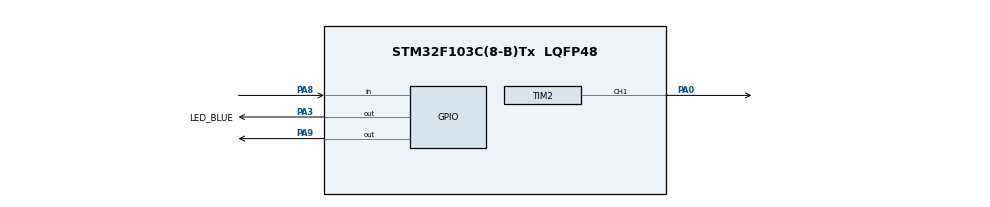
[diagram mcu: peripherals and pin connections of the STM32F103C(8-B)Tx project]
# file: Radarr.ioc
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Mcu.Family=STM32F1
Mcu.Name=STM32F103C(8-B)Tx
Mcu.Package=LQFP48
NVIC.PriorityGroup=NVIC_PRIORITYGROUP_4
PA0-WKUP.Signal=S_TIM2_CH1_ETR
PA13.Mode=Serial_Wire
PA13.Signal=SYS_JTMS-SWDIO
PA14.Mode=Serial_Wire
PA14.Signal=SYS_JTCK-SWCLK
PA3.GPIO_Label=LED_BLUE
PA3.Signal=GPIO_Output
PA8.Signal=GPIO_Input
PA9.Signal=GPIO_Output
PD0-OSC_IN.Mode=HSE-External-Oscillator
PD0-OSC_IN.Signal=RCC_OSC_IN
PD1-OSC_OUT.Mode=HSE-External-Oscillator
PD1-OSC_OUT.Signal=RCC_OSC_OUT
ProjectManager.HeapSize=0x200
ProjectManager.StackSize=0x400
ProjectManager.TargetToolchain=STM32CubeIDE
RCC.APB1Freq_Value=8000000
RCC.APB2Freq_Value=8000000
SH.S_TIM2_CH1_ETR.0=TIM2_CH1,PWM Generation1 CH1
TIM1.Prescaler=71
TIM2.Channel-PWM\ Generation1\ CH1=TIM_CHANNEL_1
TIM2.Prescaler=20
VP_TIM1_VS_ClockSourceINT.Mode=Internal
VP_TIM2_VS_ClockSourceINT.Mode=Internal
board=custom

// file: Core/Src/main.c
/* USER CODE BEGIN Header */
/**
  ******************************************************************************
  * @file           : main.c
  * @brief          : Main program body
  ******************************************************************************
  * @attention
  *
  * Copyright (c) 2025 STMicroelectronics.
  * All rights reserved.
  *
  * This software is licensed under terms that can be found in the LICENSE file
  * in the root directory of this software component.
  * If no LICENSE file comes with this software, it is provided AS-IS.
  *
  ******************************************************************************
  */
/* USER CODE END Header */
#include "main.h"

/* USER CODE BEGIN Includes */
#include <stdbool.h>
/* USER CODE END Includes */

/* USER CODE BEGIN PD */
#define TRIG_PIN GPIO_PIN_9
#define TRIG_PORT GPIOA
#define	ECHO_PIN GPIO_PIN_8
#define	ECHO_PORT GPIOA
/* USER CODE END PD */

TIM_HandleTypeDef htim1;
TIM_HandleTypeDef htim2;

/* USER CODE BEGIN PV */

//servo var
int32_t pwm_val = 0;
bool direction = 0;
//servo var

//distance meter var
uint32_t pMillis;
uint32_t Value1 = 0;
uint32_t Value2 = 0;
uint16_t Distance = 0; //cm
//distance meter var

/* USER CODE END PV */

void SystemClock_Config(void);
static void MX_GPIO_Init(void);
static void MX_TIM1_Init(void);
static void MX_TIM2_Init(void);
/* USER CODE BEGIN PFP */
void calculate_distance();
/* USER CODE END PFP */

int main(void)
{

  /* MCU Configuration--------------------------------------------------------*/

  /* Reset of all peripherals, Initializes the Flash interface and the Systick. */
  HAL_Init();

  /* Configure the system clock */
  SystemClock_Config();

  /* Initialize all configured peripherals */
  MX_GPIO_Init();
  MX_TIM1_Init();
  MX_TIM2_Init();
  /* USER CODE BEGIN 2 */

  HAL_TIM_PWM_Start(&htim2, TIM_CHANNEL_1);

  HAL_TIM_Base_Start(&htim1);
  HAL_GPIO_WritePin(TRIG_PORT, TRIG_PIN, GPIO_PIN_RESET);

  /* USER CODE END 2 */

  /* Infinite loop */
  /* USER CODE BEGIN WHILE */
  while (1)
  {
	  if(pwm_val < 1920){
		  direction = 1;
	  }
	  else if(pwm_val > 7680){
		  direction = 0;
	  }
	  if(direction) {
		  pwm_val += 5;
	  }
	  else {
		  pwm_val -= 5;
	  }

	  __HAL_TIM_SET_COMPARE(&htim2, TIM_CHANNEL_1, pwm_val);
	  calculate_distance();
	  HAL_Delay(1);

    /* USER CODE END WHILE */

  }
}

void calculate_distance() {
	HAL_GPIO_WritePin(TRIG_PORT, TRIG_PIN, GPIO_PIN_RESET);
	HAL_Delay(2); // Stabilizasyon için küçük gecikme
	HAL_GPIO_WritePin(TRIG_PORT, TRIG_PIN, GPIO_PIN_SET);
	HAL_Delay(0.01); // 10 mikro saniye TRIG HIGH
    HAL_GPIO_WritePin(TRIG_PORT, TRIG_PIN, GPIO_PIN_RESET);

	uint32_t timeout = HAL_GetTick();
	while (HAL_GPIO_ReadPin(ECHO_PORT, ECHO_PIN) == GPIO_PIN_RESET) {
	    if (HAL_GetTick() - timeout > 5) break; // 5 ms timeout
	}
	Value1 = __HAL_TIM_GET_COUNTER(&htim1);

	timeout = HAL_GetTick();
	while (HAL_GPIO_ReadPin(ECHO_PORT, ECHO_PIN) == GPIO_PIN_SET) {
	    if (HAL_GetTick() - timeout > 20) break; // 20 ms timeout
	}
	Value2 = __HAL_TIM_GET_COUNTER(&htim1);

	int32_t time_diff = Value2 - Value1;
	if (time_diff < 0) time_diff += __HAL_TIM_GET_AUTORELOAD(&htim1); // Timer taşmasına karşı
	Distance = (float)time_diff * 0.034 / 2;
	HAL_GPIO_WritePin(GPIOA, GPIO_PIN_3, (Distance < 5) ? GPIO_PIN_SET : GPIO_PIN_RESET);
}

void SystemClock_Config(void)
{
  RCC_OscInitTypeDef RCC_OscInitStruct = {0};
  RCC_ClkInitTypeDef RCC_ClkInitStruct = {0};

  /** Initializes the RCC Oscillators according to the specified parameters
  * in the RCC_OscInitTypeDef structure.
  */
  RCC_OscInitStruct.OscillatorType = RCC_OSCILLATORTYPE_HSE;
  RCC_OscInitStruct.HSEState = RCC_HSE_ON;
  RCC_OscInitStruct.HSEPredivValue = RCC_HSE_PREDIV_DIV1;
  RCC_OscInitStruct.HSIState = RCC_HSI_ON;
  RCC_OscInitStruct.PLL.PLLState = RCC_PLL_ON;
  RCC_OscInitStruct.PLL.PLLSource = RCC_PLLSOURCE_HSE;
  RCC_OscInitStruct.PLL.PLLMUL = RCC_PLL_MUL9;
  if (HAL_RCC_OscConfig(&RCC_OscInitStruct) != HAL_OK)
  {
    Error_Handler();
  }

  /** Initializes the CPU, AHB and APB buses clocks
  */
  RCC_ClkInitStruct.ClockType = RCC_CLOCKTYPE_HCLK|RCC_CLOCKTYPE_SYSCLK
                              |RCC_CLOCKTYPE_PCLK1|RCC_CLOCKTYPE_PCLK2;
  RCC_ClkInitStruct.SYSCLKSource = RCC_SYSCLKSOURCE_PLLCLK;
  RCC_ClkInitStruct.AHBCLKDivider = RCC_SYSCLK_DIV1;
  RCC_ClkInitStruct.APB1CLKDivider = RCC_HCLK_DIV2;
  RCC_ClkInitStruct.APB2CLKDivider = RCC_HCLK_DIV1;

  if (HAL_RCC_ClockConfig(&RCC_ClkInitStruct, FLASH_LATENCY_2) != HAL_OK)
  {
    Error_Handler();
  }
}

static void MX_TIM1_Init(void)
{

  TIM_ClockConfigTypeDef sClockSourceConfig = {0};
  TIM_MasterConfigTypeDef sMasterConfig = {0};

  htim1.Instance = TIM1;
  htim1.Init.Prescaler = 71;
  htim1.Init.CounterMode = TIM_COUNTERMODE_UP;
  htim1.Init.Period = 65535;
  htim1.Init.ClockDivision = TIM_CLOCKDIVISION_DIV1;
  htim1.Init.RepetitionCounter = 0;
  htim1.Init.AutoReloadPreload = TIM_AUTORELOAD_PRELOAD_DISABLE;
  if (HAL_TIM_Base_Init(&htim1) != HAL_OK)
  {
    Error_Handler();
  }
  sClockSourceConfig.ClockSource = TIM_CLOCKSOURCE_INTERNAL;
  if (HAL_TIM_ConfigClockSource(&htim1, &sClockSourceConfig) != HAL_OK)
  {
    Error_Handler();
  }
  sMasterConfig.MasterOutputTrigger = TIM_TRGO_RESET;
  sMasterConfig.MasterSlaveMode = TIM_MASTERSLAVEMODE_DISABLE;
  if (HAL_TIMEx_MasterConfigSynchronization(&htim1, &sMasterConfig) != HAL_OK)
  {
    Error_Handler();
  }

}

static void MX_TIM2_Init(void)
{

  TIM_ClockConfigTypeDef sClockSourceConfig = {0};
  TIM_MasterConfigTypeDef sMasterConfig = {0};
  TIM_OC_InitTypeDef sConfigOC = {0};

  htim2.Instance = TIM2;
  htim2.Init.Prescaler = 20;
  htim2.Init.CounterMode = TIM_COUNTERMODE_UP;
  htim2.Init.Period = 65535;
  htim2.Init.ClockDivision = TIM_CLOCKDIVISION_DIV1;
  htim2.Init.AutoReloadPreload = TIM_AUTORELOAD_PRELOAD_DISABLE;
  if (HAL_TIM_Base_Init(&htim2) != HAL_OK)
  {
    Error_Handler();
  }
  sClockSourceConfig.ClockSource = TIM_CLOCKSOURCE_INTERNAL;
  if (HAL_TIM_ConfigClockSource(&htim2, &sClockSourceConfig) != HAL_OK)
  {
    Error_Handler();
  }
  if (HAL_TIM_PWM_Init(&htim2) != HAL_OK)
  {
    Error_Handler();
  }
  sMasterConfig.MasterOutputTrigger = TIM_TRGO_RESET;
  sMasterConfig.MasterSlaveMode = TIM_MASTERSLAVEMODE_DISABLE;
  if (HAL_TIMEx_MasterConfigSynchronization(&htim2, &sMasterConfig) != HAL_OK)
  {
    Error_Handler();
  }
  sConfigOC.OCMode = TIM_OCMODE_PWM1;
  sConfigOC.Pulse = 0;
  sConfigOC.OCPolarity = TIM_OCPOLARITY_HIGH;
  sConfigOC.OCFastMode = TIM_OCFAST_DISABLE;
  if (HAL_TIM_PWM_ConfigChannel(&htim2, &sConfigOC, TIM_CHANNEL_1) != HAL_OK)
  {
    Error_Handler();
  }
  HAL_TIM_MspPostInit(&htim2);

}

static void MX_GPIO_Init(void)
{
  GPIO_InitTypeDef GPIO_InitStruct = {0};

  /* GPIO Ports Clock Enable */
  __HAL_RCC_GPIOD_CLK_ENABLE();
  __HAL_RCC_GPIOA_CLK_ENABLE();

  /*Configure GPIO pin Output Level */
  HAL_GPIO_WritePin(GPIOA, LED_BLUE_Pin|GPIO_PIN_9, GPIO_PIN_RESET);

  /*Configure GPIO pins : LED_BLUE_Pin PA9 */
  GPIO_InitStruct.Pin = LED_BLUE_Pin|GPIO_PIN_9;
  GPIO_InitStruct.Mode = GPIO_MODE_OUTPUT_PP;
  GPIO_InitStruct.Pull = GPIO_NOPULL;
  GPIO_InitStruct.Speed = GPIO_SPEED_FREQ_LOW;
  HAL_GPIO_Init(GPIOA, &GPIO_InitStruct);

  /*Configure GPIO pin : PA8 */
  GPIO_InitStruct.Pin = GPIO_PIN_8;
  GPIO_InitStruct.Mode = GPIO_MODE_INPUT;
  GPIO_InitStruct.Pull = GPIO_NOPULL;
  HAL_GPIO_Init(GPIOA, &GPIO_InitStruct);

}

void Error_Handler(void)
{
  __disable_irq();
  while (1)
  {
  }
}
